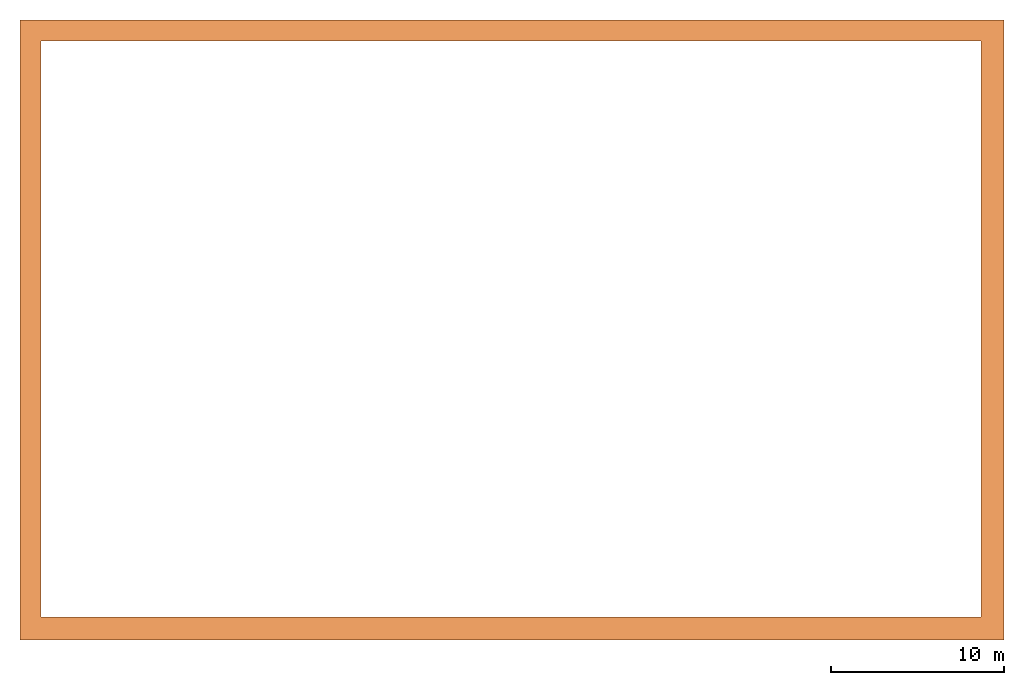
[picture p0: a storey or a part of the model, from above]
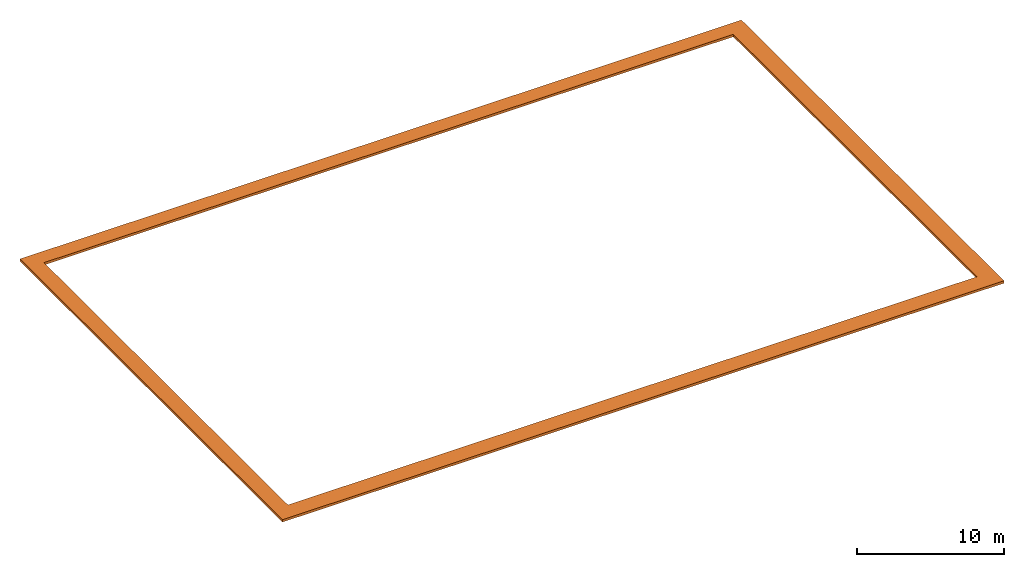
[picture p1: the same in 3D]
Properties of the parts of a building model (IFC4)

# File
Description: ViewDefinition [CoordinationView]
Time: 2026-09-10T21:22:48
Written by: IfcOpenShell 0.8.0
Made in: IfcOpenShell 0.8.0

# IfcBuilding, INNOCEAN
Pset_ConversionAssumptions - ModelStatus: Preliminary - PDF derived, geometry not construction verified; Heights: Storey elevations, slab thickness and facade heights are assumed; Source: 정림3도면_01. 평면도.pdf; 28 pages; X span 53100mm Y span 32600mm

# IfcBuildingStorey (28)
In: INNOCEAN
Name | Elevation (mm)
B8 | -30600
B7 | -27000
B6 | -23400
B5 | -19800
B4 | -16200
B3 | -12600
B2 | -9000
B1 | -5000
F01 | 0
F02 | 6000
F03 | 11000
F04 | 15800
F05 | 20600
F06 | 25400
F07 | 30200
F08 | 34400
F09 | 38600
F10 | 42800
F11 | 47000
F12 | 51200
F13 | 55400
F14 | 59600
F15 | 63800
F16 | 68000
F17 | 72200
F18 | 76400
F19 | 80600
RF | 84800

# IfcBuildingElementProxy (4)
Name | In | Description
F18_Garden_F18_001 | F18 | Simplified footprint from colored landscape area
F19_Garden_F19_001 | F19 | Simplified footprint from colored landscape area
RF_Garden_RF_001 | RF | Simplified footprint from colored landscape area
Site_SiteEdge_001 | Site | Site boundary traced from PDF, no terrain elevations

# IfcColumn (342)
Description: PDF vector recovery
Name | In
B8_Columns_B8_001 | B8
B8_Columns_B8_002 | B8
B8_Columns_B8_003 | B8
B8_Columns_B8_004 | B8
B8_Columns_B8_005 | B8
B8_Columns_B8_006 | B8
B8_Columns_B8_007 | B8
B8_Columns_B8_008 | B8
B8_Columns_B8_009 | B8
B8_Columns_B8_010 | B8
B8_Columns_B8_011 | B8
B8_Columns_B8_012 | B8
B8_Columns_B8_013 | B8
B8_Columns_B8_014 | B8
B8_Columns_B8_015 | B8
B8_Columns_B8_016 | B8
B8_Columns_B8_017 | B8
B8_Columns_B8_018 | B8
B8_Columns_B8_019 | B8
B8_Columns_B8_020 | B8
B8_Columns_B8_021 | B8
B7_Columns_B7_001 | B7
B7_Columns_B7_002 | B7
B7_Columns_B7_003 | B7
B7_Columns_B7_004 | B7
B7_Columns_B7_005 | B7
B7_Columns_B7_006 | B7
B7_Columns_B7_007 | B7
B7_Columns_B7_008 | B7
B7_Columns_B7_009 | B7
B7_Columns_B7_010 | B7
B7_Columns_B7_011 | B7
B7_Columns_B7_012 | B7
B7_Columns_B7_013 | B7
B7_Columns_B7_014 | B7
B7_Columns_B7_015 | B7
B7_Columns_B7_016 | B7
B7_Columns_B7_017 | B7
B7_Columns_B7_018 | B7
B7_Columns_B7_019 | B7
B7_Columns_B7_020 | B7
B7_Columns_B7_021 | B7
B6_Columns_B6_001 | B6
B6_Columns_B6_002 | B6
B6_Columns_B6_003 | B6
B6_Columns_B6_004 | B6
B6_Columns_B6_005 | B6
B6_Columns_B6_006 | B6
B6_Columns_B6_007 | B6
B6_Columns_B6_008 | B6
B6_Columns_B6_009 | B6
B6_Columns_B6_010 | B6
B6_Columns_B6_011 | B6
B6_Columns_B6_012 | B6
B6_Columns_B6_013 | B6
B6_Columns_B6_014 | B6
B6_Columns_B6_015 | B6
B6_Columns_B6_016 | B6
B6_Columns_B6_017 | B6
B6_Columns_B6_018 | B6
B6_Columns_B6_019 | B6
B6_Columns_B6_020 | B6
B6_Columns_B6_021 | B6
B5_Columns_B5_001 | B5
B5_Columns_B5_002 | B5
B5_Columns_B5_003 | B5
B5_Columns_B5_004 | B5
B5_Columns_B5_005 | B5
B5_Columns_B5_006 | B5
B5_Columns_B5_007 | B5
B5_Columns_B5_008 | B5
B5_Columns_B5_009 | B5
B5_Columns_B5_010 | B5
B5_Columns_B5_011 | B5
B5_Columns_B5_012 | B5
B5_Columns_B5_013 | B5
B5_Columns_B5_014 | B5
B5_Columns_B5_015 | B5
B5_Columns_B5_016 | B5
B5_Columns_B5_017 | B5
B5_Columns_B5_018 | B5
B5_Columns_B5_019 | B5
B5_Columns_B5_020 | B5
B5_Columns_B5_021 | B5
B4_Columns_B4_001 | B4
B4_Columns_B4_002 | B4
B4_Columns_B4_003 | B4
B4_Columns_B4_004 | B4
B4_Columns_B4_005 | B4
B4_Columns_B4_006 | B4
B4_Columns_B4_007 | B4
B4_Columns_B4_008 | B4
B4_Columns_B4_009 | B4
B4_Columns_B4_010 | B4
B4_Columns_B4_011 | B4
B4_Columns_B4_012 | B4
B4_Columns_B4_013 | B4
B4_Columns_B4_014 | B4
B4_Columns_B4_015 | B4
B4_Columns_B4_016 | B4
B4_Columns_B4_017 | B4
B4_Columns_B4_018 | B4
B4_Columns_B4_019 | B4
B4_Columns_B4_020 | B4
B3_Columns_B3_001 | B3
B3_Columns_B3_002 | B3
B3_Columns_B3_003 | B3
B3_Columns_B3_004 | B3
B3_Columns_B3_005 | B3
B3_Columns_B3_006 | B3
B3_Columns_B3_007 | B3
B3_Columns_B3_008 | B3
B3_Columns_B3_009 | B3
B3_Columns_B3_010 | B3
B3_Columns_B3_011 | B3
B3_Columns_B3_012 | B3
B3_Columns_B3_013 | B3
B3_Columns_B3_014 | B3
B3_Columns_B3_015 | B3
B3_Columns_B3_016 | B3
B3_Columns_B3_017 | B3
B3_Columns_B3_018 | B3
B3_Columns_B3_019 | B3
B3_Columns_B3_020 | B3
B3_Columns_B3_021 | B3
B2_Columns_B2_001 | B2
B2_Columns_B2_002 | B2
B2_Columns_B2_003 | B2
B2_Columns_B2_004 | B2
B2_Columns_B2_005 | B2
B2_Columns_B2_006 | B2
B2_Columns_B2_007 | B2
B2_Columns_B2_008 | B2
B2_Columns_B2_009 | B2
B2_Columns_B2_010 | B2
B2_Columns_B2_011 | B2
B2_Columns_B2_012 | B2
B1_Columns_B1_001 | B1
B1_Columns_B1_002 | B1
B1_Columns_B1_003 | B1
B1_Columns_B1_004 | B1
B1_Columns_B1_005 | B1
B1_Columns_B1_006 | B1
B1_Columns_B1_007 | B1
B1_Columns_B1_008 | B1
B1_Columns_B1_009 | B1
B1_Columns_B1_010 | B1
B1_Columns_B1_011 | B1
B1_Columns_B1_012 | B1
B1_Columns_B1_013 | B1
B1_Columns_B1_014 | B1
F01_Columns_F01_001 | F01
F01_Columns_F01_002 | F01
F01_Columns_F01_003 | F01
F01_Columns_F01_004 | F01
F01_Columns_F01_005 | F01
F01_Columns_F01_006 | F01
F01_Columns_F01_007 | F01
F01_Columns_F01_008 | F01
F01_Columns_F01_009 | F01
F01_Columns_F01_010 | F01
F01_Columns_F01_011 | F01
F02_Columns_F02_001 | F02
F02_Columns_F02_002 | F02
F02_Columns_F02_003 | F02
F02_Columns_F02_004 | F02
F02_Columns_F02_005 | F02
F02_Columns_F02_006 | F02
F02_Columns_F02_007 | F02
F02_Columns_F02_008 | F02
F02_Columns_F02_009 | F02
F02_Columns_F02_010 | F02
F03_Columns_F03_001 | F03
F03_Columns_F03_002 | F03
F03_Columns_F03_003 | F03
F03_Columns_F03_004 | F03
F03_Columns_F03_005 | F03
F03_Columns_F03_006 | F03
F03_Columns_F03_007 | F03
F03_Columns_F03_008 | F03
F03_Columns_F03_009 | F03
F03_Columns_F03_010 | F03
F04_Columns_F04_001 | F04
F04_Columns_F04_002 | F04
F04_Columns_F04_003 | F04
F04_Columns_F04_004 | F04
F04_Columns_F04_005 | F04
F04_Columns_F04_006 | F04
F04_Columns_F04_007 | F04
F04_Columns_F04_008 | F04
F04_Columns_F04_009 | F04
F04_Columns_F04_010 | F04
F05_Columns_F05_001 | F05
F05_Columns_F05_002 | F05
F05_Columns_F05_003 | F05
F05_Columns_F05_004 | F05
F05_Columns_F05_005 | F05
F05_Columns_F05_006 | F05
F05_Columns_F05_007 | F05
F05_Columns_F05_008 | F05
F05_Columns_F05_009 | F05
F05_Columns_F05_010 | F05
F05_Columns_F05_011 | F05
F06_Columns_F06_001 | F06
F06_Columns_F06_002 | F06
F06_Columns_F06_003 | F06
F06_Columns_F06_004 | F06
F06_Columns_F06_005 | F06
F06_Columns_F06_006 | F06
F06_Columns_F06_007 | F06
F06_Columns_F06_008 | F06
F06_Columns_F06_009 | F06
F06_Columns_F06_010 | F06
F07_Columns_F07_001 | F07
F07_Columns_F07_002 | F07
F07_Columns_F07_003 | F07
F07_Columns_F07_004 | F07
F07_Columns_F07_005 | F07
F07_Columns_F07_006 | F07
F07_Columns_F07_007 | F07
F07_Columns_F07_008 | F07
F07_Columns_F07_009 | F07
F07_Columns_F07_010 | F07
F08_Columns_F08_001 | F08
F08_Columns_F08_002 | F08
F08_Columns_F08_003 | F08
F08_Columns_F08_004 | F08
F08_Columns_F08_005 | F08
F08_Columns_F08_006 | F08
F08_Columns_F08_007 | F08
F08_Columns_F08_008 | F08
F08_Columns_F08_009 | F08
F08_Columns_F08_010 | F08
F09_Columns_F09_001 | F09
F09_Columns_F09_002 | F09
F09_Columns_F09_003 | F09
F09_Columns_F09_004 | F09
F09_Columns_F09_005 | F09
F09_Columns_F09_006 | F09
F09_Columns_F09_007 | F09
F09_Columns_F09_008 | F09
F09_Columns_F09_009 | F09
F09_Columns_F09_010 | F09
F10_Columns_F10_001 | F10
F10_Columns_F10_002 | F10
F10_Columns_F10_003 | F10
F10_Columns_F10_004 | F10
F10_Columns_F10_005 | F10
F10_Columns_F10_006 | F10
F10_Columns_F10_007 | F10
F10_Columns_F10_008 | F10
F10_Columns_F10_009 | F10
F10_Columns_F10_010 | F10
F11_Columns_F11_001 | F11
F11_Columns_F11_002 | F11
F11_Columns_F11_003 | F11
F11_Columns_F11_004 | F11
F11_Columns_F11_005 | F11
F11_Columns_F11_006 | F11
F11_Columns_F11_007 | F11
F11_Columns_F11_008 | F11
F11_Columns_F11_009 | F11
F11_Columns_F11_010 | F11
F12_Columns_F12_001 | F12
F12_Columns_F12_002 | F12
F12_Columns_F12_003 | F12
F12_Columns_F12_004 | F12
F12_Columns_F12_005 | F12
F12_Columns_F12_006 | F12
F12_Columns_F12_007 | F12
F12_Columns_F12_008 | F12
F12_Columns_F12_009 | F12
F12_Columns_F12_010 | F12
F13_Columns_F13_001 | F13
F13_Columns_F13_002 | F13
F13_Columns_F13_003 | F13
F13_Columns_F13_004 | F13
F13_Columns_F13_005 | F13
F13_Columns_F13_006 | F13
F13_Columns_F13_007 | F13
F13_Columns_F13_008 | F13
F13_Columns_F13_009 | F13
F13_Columns_F13_010 | F13
F14_Columns_F14_001 | F14
F14_Columns_F14_002 | F14
F14_Columns_F14_003 | F14
F14_Columns_F14_004 | F14
F14_Columns_F14_005 | F14
F14_Columns_F14_006 | F14
F14_Columns_F14_007 | F14
F14_Columns_F14_008 | F14
F14_Columns_F14_009 | F14
F14_Columns_F14_010 | F14
F15_Columns_F15_001 | F15
F15_Columns_F15_002 | F15
F15_Columns_F15_003 | F15
F15_Columns_F15_004 | F15
F15_Columns_F15_005 | F15
F15_Columns_F15_006 | F15
F15_Columns_F15_007 | F15
F15_Columns_F15_008 | F15
F15_Columns_F15_009 | F15
F15_Columns_F15_010 | F15
F16_Columns_F16_001 | F16
F16_Columns_F16_002 | F16
F16_Columns_F16_003 | F16
F16_Columns_F16_004 | F16
F16_Columns_F16_005 | F16
F16_Columns_F16_006 | F16
F16_Columns_F16_007 | F16
F16_Columns_F16_008 | F16
F16_Columns_F16_009 | F16
F16_Columns_F16_010 | F16
F17_Columns_F17_001 | F17
F17_Columns_F17_002 | F17
F17_Columns_F17_003 | F17
F17_Columns_F17_004 | F17
F17_Columns_F17_005 | F17
F17_Columns_F17_006 | F17
F17_Columns_F17_007 | F17
F17_Columns_F17_008 | F17
F17_Columns_F17_009 | F17
F17_Columns_F17_010 | F17
F18_Columns_F18_001 | F18
F18_Columns_F18_002 | F18
F18_Columns_F18_003 | F18
F18_Columns_F18_004 | F18
F18_Columns_F18_005 | F18
F18_Columns_F18_006 | F18
F18_Columns_F18_007 | F18
F18_Columns_F18_008 | F18
F18_Columns_F18_009 | F18
F18_Columns_F18_010 | F18
F19_Columns_F19_001 | F19
F19_Columns_F19_002 | F19
F19_Columns_F19_003 | F19
F19_Columns_F19_004 | F19
F19_Columns_F19_005 | F19
F19_Columns_F19_006 | F19
F19_Columns_F19_007 | F19
F19_Columns_F19_008 | F19
F19_Columns_F19_009 | F19

# IfcCurtainWall (72)
Description: Plan envelope; generic transparent facade, no elevation data
Name | In
F02_Facade_F02_001 | F02
F02_Facade_F02_002 | F02
F02_Facade_F02_003 | F02
F02_Facade_F02_004 | F02
F03_Facade_F03_001 | F03
F03_Facade_F03_002 | F03
F03_Facade_F03_003 | F03
F03_Facade_F03_004 | F03
F04_Facade_F04_001 | F04
F04_Facade_F04_002 | F04
F04_Facade_F04_003 | F04
F04_Facade_F04_004 | F04
F05_Facade_F05_001 | F05
F05_Facade_F05_002 | F05
F05_Facade_F05_003 | F05
F05_Facade_F05_004 | F05
F06_Facade_F06_001 | F06
F06_Facade_F06_002 | F06
F06_Facade_F06_003 | F06
F06_Facade_F06_004 | F06
F07_Facade_F07_001 | F07
F07_Facade_F07_002 | F07
F07_Facade_F07_003 | F07
F07_Facade_F07_004 | F07
F08_Facade_F08_001 | F08
F08_Facade_F08_002 | F08
F08_Facade_F08_003 | F08
F08_Facade_F08_004 | F08
F09_Facade_F09_001 | F09
F09_Facade_F09_002 | F09
F09_Facade_F09_003 | F09
F09_Facade_F09_004 | F09
F10_Facade_F10_001 | F10
F10_Facade_F10_002 | F10
F10_Facade_F10_003 | F10
F10_Facade_F10_004 | F10
F11_Facade_F11_001 | F11
F11_Facade_F11_002 | F11
F11_Facade_F11_003 | F11
F11_Facade_F11_004 | F11
F12_Facade_F12_001 | F12
F12_Facade_F12_002 | F12
F12_Facade_F12_003 | F12
F12_Facade_F12_004 | F12
F13_Facade_F13_001 | F13
F13_Facade_F13_002 | F13
F13_Facade_F13_003 | F13
F13_Facade_F13_004 | F13
F14_Facade_F14_001 | F14
F14_Facade_F14_002 | F14
F14_Facade_F14_003 | F14
F14_Facade_F14_004 | F14
F15_Facade_F15_001 | F15
F15_Facade_F15_002 | F15
F15_Facade_F15_003 | F15
F15_Facade_F15_004 | F15
F16_Facade_F16_001 | F16
F16_Facade_F16_002 | F16
F16_Facade_F16_003 | F16
F16_Facade_F16_004 | F16
F17_Facade_F17_001 | F17
F17_Facade_F17_002 | F17
F17_Facade_F17_003 | F17
F17_Facade_F17_004 | F17
F18_Facade_F18_001 | F18
F18_Facade_F18_002 | F18
F18_Facade_F18_003 | F18
F18_Facade_F18_004 | F18
F19_Facade_F19_001 | F19
F19_Facade_F19_002 | F19
F19_Facade_F19_003 | F19
F19_Facade_F19_004 | F19

# IfcSlab (28)
Description: Footprint and voids visually traced; thickness assumed 250 mm
Name | In
B8_Slab_B8_001 | B8
B7_Slab_B7_001 | B7
B6_Slab_B6_001 | B6
B5_Slab_B5_001 | B5
B4_Slab_B4_001 | B4
B3_Slab_B3_001 | B3
B2_Slab_B2_001 | B2
B1_Slab_B1_001 | B1
F01_Slab_F01_001 | F01
F02_Slab_F02_001 | F02
F03_Slab_F03_001 | F03
F04_Slab_F04_001 | F04
F05_Slab_F05_001 | F05
F06_Slab_F06_001 | F06
F07_Slab_F07_001 | F07
F08_Slab_F08_001 | F08
F09_Slab_F09_001 | F09
F10_Slab_F10_001 | F10
F11_Slab_F11_001 | F11
F12_Slab_F12_001 | F12
F13_Slab_F13_001 | F13
F14_Slab_F14_001 | F14
F15_Slab_F15_001 | F15
F16_Slab_F16_001 | F16
F17_Slab_F17_001 | F17
F18_Slab_F18_001 | F18
F19_Slab_F19_001 | F19
RF_Slab_RF_001 | RF

# IfcWall (2039)
Description: Wall-layer closed loops and paired parallel lines 75-425 mm; incomplete/unclassified partitions remain in reference
Name | In
B8_Walls_B8_001 | B8
B8_Walls_B8_002 | B8
B8_Walls_B8_003 | B8
B8_Walls_B8_004 | B8
B8_Walls_B8_005 | B8
B8_Walls_B8_006 | B8
B8_Walls_B8_007 | B8
B8_Walls_B8_008 | B8
B8_Walls_B8_009 | B8
B8_Walls_B8_010 | B8
B8_Walls_B8_011 | B8
B8_Walls_B8_012 | B8
B8_Walls_B8_013 | B8
B8_Walls_B8_014 | B8
B8_Walls_B8_015 | B8
B8_Walls_B8_016 | B8
B8_Walls_B8_017 | B8
B8_Walls_B8_018 | B8
B8_Walls_B8_019 | B8
B8_Walls_B8_020 | B8
B8_Walls_B8_021 | B8
B8_Walls_B8_022 | B8
B8_Walls_B8_023 | B8
B8_Walls_B8_024 | B8
B8_Walls_B8_025 | B8
B8_Walls_B8_026 | B8
B8_Walls_B8_027 | B8
B8_Walls_B8_028 | B8
B8_Walls_B8_029 | B8
B8_Walls_B8_030 | B8
B8_Walls_B8_031 | B8
B8_Walls_B8_032 | B8
B8_Walls_B8_033 | B8
B8_Walls_B8_034 | B8
B8_Walls_B8_035 | B8
B8_Walls_B8_036 | B8
B8_Walls_B8_037 | B8
B8_Walls_B8_038 | B8
B8_Walls_B8_039 | B8
B8_Walls_B8_040 | B8
B8_Walls_B8_041 | B8
B8_Walls_B8_042 | B8
B8_Walls_B8_043 | B8
B8_Walls_B8_044 | B8
B8_Walls_B8_045 | B8
B8_Walls_B8_046 | B8
B8_Walls_B8_047 | B8
B8_Walls_B8_048 | B8
B8_Walls_B8_049 | B8
B8_Walls_B8_050 | B8
B8_Walls_B8_051 | B8
B8_Walls_B8_052 | B8
B8_Walls_B8_053 | B8
B8_Walls_B8_054 | B8
B8_Walls_B8_055 | B8
B8_Walls_B8_056 | B8
B8_Walls_B8_057 | B8
B8_Walls_B8_058 | B8
B8_Walls_B8_059 | B8
B8_Walls_B8_060 | B8
B8_Walls_B8_061 | B8
B8_Walls_B8_062 | B8
B8_Walls_B8_063 | B8
B7_Walls_B7_001 | B7
B7_Walls_B7_002 | B7
B7_Walls_B7_003 | B7
B7_Walls_B7_004 | B7
B7_Walls_B7_005 | B7
B7_Walls_B7_006 | B7
B7_Walls_B7_007 | B7
B7_Walls_B7_008 | B7
B7_Walls_B7_009 | B7
B7_Walls_B7_010 | B7
B7_Walls_B7_011 | B7
B7_Walls_B7_012 | B7
B7_Walls_B7_013 | B7
B7_Walls_B7_014 | B7
B7_Walls_B7_015 | B7
B7_Walls_B7_016 | B7
B7_Walls_B7_017 | B7
B7_Walls_B7_018 | B7
B7_Walls_B7_019 | B7
B7_Walls_B7_020 | B7
B7_Walls_B7_021 | B7
B7_Walls_B7_022 | B7
B7_Walls_B7_023 | B7
B7_Walls_B7_024 | B7
B7_Walls_B7_025 | B7
B7_Walls_B7_026 | B7
B7_Walls_B7_027 | B7
B7_Walls_B7_028 | B7
B7_Walls_B7_029 | B7
B7_Walls_B7_030 | B7
B7_Walls_B7_031 | B7
B7_Walls_B7_032 | B7
B7_Walls_B7_033 | B7
B7_Walls_B7_034 | B7
B7_Walls_B7_035 | B7
B7_Walls_B7_036 | B7
B7_Walls_B7_037 | B7
B7_Walls_B7_038 | B7
B7_Walls_B7_039 | B7
B7_Walls_B7_040 | B7
B7_Walls_B7_041 | B7
B7_Walls_B7_042 | B7
B7_Walls_B7_043 | B7
B7_Walls_B7_044 | B7
B7_Walls_B7_045 | B7
B7_Walls_B7_046 | B7
B7_Walls_B7_047 | B7
B7_Walls_B7_048 | B7
B7_Walls_B7_049 | B7
B7_Walls_B7_050 | B7
B7_Walls_B7_051 | B7
B7_Walls_B7_052 | B7
B7_Walls_B7_053 | B7
B7_Walls_B7_054 | B7
B7_Walls_B7_055 | B7
B7_Walls_B7_056 | B7
B6_Walls_B6_001 | B6
B6_Walls_B6_002 | B6
B6_Walls_B6_003 | B6
B6_Walls_B6_004 | B6
B6_Walls_B6_005 | B6
B6_Walls_B6_006 | B6
B6_Walls_B6_007 | B6
B6_Walls_B6_008 | B6
B6_Walls_B6_009 | B6
B6_Walls_B6_010 | B6
B6_Walls_B6_011 | B6
B6_Walls_B6_012 | B6
B6_Walls_B6_013 | B6
B6_Walls_B6_014 | B6
B6_Walls_B6_015 | B6
B6_Walls_B6_016 | B6
B6_Walls_B6_017 | B6
B6_Walls_B6_018 | B6
B6_Walls_B6_019 | B6
B6_Walls_B6_020 | B6
B6_Walls_B6_021 | B6
B6_Walls_B6_022 | B6
B6_Walls_B6_023 | B6
B6_Walls_B6_024 | B6
B6_Walls_B6_025 | B6
B6_Walls_B6_026 | B6
B6_Walls_B6_027 | B6
B6_Walls_B6_028 | B6
B6_Walls_B6_029 | B6
B6_Walls_B6_030 | B6
B6_Walls_B6_031 | B6
B6_Walls_B6_032 | B6
B6_Walls_B6_033 | B6
B6_Walls_B6_034 | B6
B6_Walls_B6_035 | B6
B6_Walls_B6_036 | B6
B6_Walls_B6_037 | B6
B6_Walls_B6_038 | B6
B6_Walls_B6_039 | B6
B6_Walls_B6_040 | B6
B6_Walls_B6_041 | B6
B6_Walls_B6_042 | B6
B6_Walls_B6_043 | B6
B6_Walls_B6_044 | B6
B6_Walls_B6_045 | B6
B6_Walls_B6_046 | B6
B6_Walls_B6_047 | B6
B6_Walls_B6_048 | B6
B6_Walls_B6_049 | B6
B6_Walls_B6_050 | B6
B6_Walls_B6_051 | B6
B6_Walls_B6_052 | B6
B6_Walls_B6_053 | B6
B6_Walls_B6_054 | B6
B6_Walls_B6_055 | B6
B6_Walls_B6_056 | B6
B6_Walls_B6_057 | B6
B6_Walls_B6_058 | B6
B6_Walls_B6_059 | B6
B6_Walls_B6_060 | B6
B6_Walls_B6_061 | B6
B5_Walls_B5_001 | B5
B5_Walls_B5_002 | B5
B5_Walls_B5_003 | B5
B5_Walls_B5_004 | B5
B5_Walls_B5_005 | B5
B5_Walls_B5_006 | B5
B5_Walls_B5_007 | B5
B5_Walls_B5_008 | B5
B5_Walls_B5_009 | B5
B5_Walls_B5_010 | B5
B5_Walls_B5_011 | B5
B5_Walls_B5_012 | B5
B5_Walls_B5_013 | B5
B5_Walls_B5_014 | B5
B5_Walls_B5_015 | B5
B5_Walls_B5_016 | B5
B5_Walls_B5_017 | B5
B5_Walls_B5_018 | B5
B5_Walls_B5_019 | B5
B5_Walls_B5_020 | B5
B5_Walls_B5_021 | B5
B5_Walls_B5_022 | B5
B5_Walls_B5_023 | B5
B5_Walls_B5_024 | B5
B5_Walls_B5_025 | B5
B5_Walls_B5_026 | B5
B5_Walls_B5_027 | B5
B5_Walls_B5_028 | B5
B5_Walls_B5_029 | B5
B5_Walls_B5_030 | B5
B5_Walls_B5_031 | B5
B5_Walls_B5_032 | B5
B5_Walls_B5_033 | B5
B5_Walls_B5_034 | B5
B5_Walls_B5_035 | B5
B5_Walls_B5_036 | B5
B5_Walls_B5_037 | B5
B5_Walls_B5_038 | B5
B5_Walls_B5_039 | B5
B5_Walls_B5_040 | B5
B5_Walls_B5_041 | B5
B5_Walls_B5_042 | B5
B5_Walls_B5_043 | B5
B5_Walls_B5_044 | B5
B5_Walls_B5_045 | B5
B5_Walls_B5_046 | B5
B5_Walls_B5_047 | B5
B5_Walls_B5_048 | B5
B5_Walls_B5_049 | B5
B5_Walls_B5_050 | B5
B5_Walls_B5_051 | B5
B5_Walls_B5_052 | B5
B5_Walls_B5_053 | B5
B5_Walls_B5_054 | B5
B5_Walls_B5_055 | B5
B5_Walls_B5_056 | B5
B5_Walls_B5_057 | B5
B5_Walls_B5_058 | B5
B5_Walls_B5_059 | B5
B5_Walls_B5_060 | B5
B5_Walls_B5_061 | B5
B4_Walls_B4_001 | B4
B4_Walls_B4_002 | B4
B4_Walls_B4_003 | B4
B4_Walls_B4_004 | B4
B4_Walls_B4_005 | B4
B4_Walls_B4_006 | B4
B4_Walls_B4_007 | B4
B4_Walls_B4_008 | B4
B4_Walls_B4_009 | B4
B4_Walls_B4_010 | B4
B4_Walls_B4_011 | B4
B4_Walls_B4_012 | B4
B4_Walls_B4_013 | B4
B4_Walls_B4_014 | B4
B4_Walls_B4_015 | B4
B4_Walls_B4_016 | B4
B4_Walls_B4_017 | B4
B4_Walls_B4_018 | B4
B4_Walls_B4_019 | B4
B4_Walls_B4_020 | B4
B4_Walls_B4_021 | B4
B4_Walls_B4_022 | B4
B4_Walls_B4_023 | B4
B4_Walls_B4_024 | B4
B4_Walls_B4_025 | B4
B4_Walls_B4_026 | B4
B4_Walls_B4_027 | B4
B4_Walls_B4_028 | B4
B4_Walls_B4_029 | B4
B4_Walls_B4_030 | B4
B4_Walls_B4_031 | B4
B4_Walls_B4_032 | B4
B4_Walls_B4_033 | B4
B4_Walls_B4_034 | B4
B4_Walls_B4_035 | B4
B4_Walls_B4_036 | B4
B4_Walls_B4_037 | B4
B4_Walls_B4_038 | B4
B4_Walls_B4_039 | B4
B4_Walls_B4_040 | B4
B4_Walls_B4_041 | B4
B4_Walls_B4_042 | B4
B4_Walls_B4_043 | B4
B4_Walls_B4_044 | B4
B4_Walls_B4_045 | B4
B4_Walls_B4_046 | B4
B4_Walls_B4_047 | B4
B4_Walls_B4_048 | B4
B4_Walls_B4_049 | B4
B4_Walls_B4_050 | B4
B4_Walls_B4_051 | B4
B4_Walls_B4_052 | B4
B4_Walls_B4_053 | B4
B4_Walls_B4_054 | B4
B4_Walls_B4_055 | B4
B4_Walls_B4_056 | B4
B4_Walls_B4_057 | B4
B4_Walls_B4_058 | B4
B4_Walls_B4_059 | B4
B4_Walls_B4_060 | B4
B4_Walls_B4_061 | B4
B3_Walls_B3_001 | B3
B3_Walls_B3_002 | B3
B3_Walls_B3_003 | B3
B3_Walls_B3_004 | B3
B3_Walls_B3_005 | B3
B3_Walls_B3_006 | B3
B3_Walls_B3_007 | B3
B3_Walls_B3_008 | B3
B3_Walls_B3_009 | B3
B3_Walls_B3_010 | B3
B3_Walls_B3_011 | B3
B3_Walls_B3_012 | B3
B3_Walls_B3_013 | B3
B3_Walls_B3_014 | B3
B3_Walls_B3_015 | B3
B3_Walls_B3_016 | B3
B3_Walls_B3_017 | B3
B3_Walls_B3_018 | B3
B3_Walls_B3_019 | B3
B3_Walls_B3_020 | B3
B3_Walls_B3_021 | B3
B3_Walls_B3_022 | B3
B3_Walls_B3_023 | B3
B3_Walls_B3_024 | B3
B3_Walls_B3_025 | B3
B3_Walls_B3_026 | B3
B3_Walls_B3_027 | B3
B3_Walls_B3_028 | B3
B3_Walls_B3_029 | B3
B3_Walls_B3_030 | B3
B3_Walls_B3_031 | B3
B3_Walls_B3_032 | B3
B3_Walls_B3_033 | B3
B3_Walls_B3_034 | B3
B3_Walls_B3_035 | B3
B3_Walls_B3_036 | B3
B3_Walls_B3_037 | B3
B3_Walls_B3_038 | B3
B3_Walls_B3_039 | B3
B3_Walls_B3_040 | B3
B3_Walls_B3_041 | B3
B3_Walls_B3_042 | B3
B3_Walls_B3_043 | B3
B3_Walls_B3_044 | B3
B3_Walls_B3_045 | B3
B3_Walls_B3_046 | B3
B3_Walls_B3_047 | B3
B3_Walls_B3_048 | B3
B3_Walls_B3_049 | B3
B3_Walls_B3_050 | B3
B3_Walls_B3_051 | B3
B3_Walls_B3_052 | B3
B3_Walls_B3_053 | B3
B3_Walls_B3_054 | B3
B3_Walls_B3_055 | B3
B3_Walls_B3_056 | B3
B3_Walls_B3_057 | B3
B3_Walls_B3_058 | B3
B3_Walls_B3_059 | B3
B3_Walls_B3_060 | B3
B3_Walls_B3_061 | B3
B2_Walls_B2_001 | B2
B2_Walls_B2_002 | B2
B2_Walls_B2_003 | B2
B2_Walls_B2_004 | B2
B2_Walls_B2_005 | B2
B2_Walls_B2_006 | B2
B2_Walls_B2_007 | B2
B2_Walls_B2_008 | B2
B2_Walls_B2_009 | B2
B2_Walls_B2_010 | B2
B2_Walls_B2_011 | B2
B2_Walls_B2_012 | B2
B2_Walls_B2_013 | B2
B2_Walls_B2_014 | B2
B2_Walls_B2_015 | B2
B2_Walls_B2_016 | B2
B2_Walls_B2_017 | B2
B2_Walls_B2_018 | B2
B2_Walls_B2_019 | B2
B2_Walls_B2_020 | B2
B2_Walls_B2_021 | B2
B2_Walls_B2_022 | B2
B2_Walls_B2_023 | B2
B2_Walls_B2_024 | B2
B2_Walls_B2_025 | B2
B2_Walls_B2_026 | B2
B2_Walls_B2_027 | B2
B2_Walls_B2_028 | B2
B2_Walls_B2_029 | B2
B2_Walls_B2_030 | B2
B2_Walls_B2_031 | B2
B2_Walls_B2_032 | B2
B2_Walls_B2_033 | B2
B2_Walls_B2_034 | B2
B2_Walls_B2_035 | B2
B2_Walls_B2_036 | B2
B2_Walls_B2_037 | B2
B2_Walls_B2_038 | B2
B2_Walls_B2_039 | B2
B2_Walls_B2_040 | B2
B2_Walls_B2_041 | B2
B2_Walls_B2_042 | B2
B2_Walls_B2_043 | B2
B2_Walls_B2_044 | B2
B2_Walls_B2_045 | B2
B2_Walls_B2_046 | B2
B2_Walls_B2_047 | B2
B2_Walls_B2_048 | B2
B2_Walls_B2_049 | B2
B2_Walls_B2_050 | B2
B2_Walls_B2_051 | B2
B2_Walls_B2_052 | B2
B2_Walls_B2_053 | B2
B2_Walls_B2_054 | B2
B2_Walls_B2_055 | B2
B2_Walls_B2_056 | B2
B2_Walls_B2_057 | B2
B2_Walls_B2_058 | B2
B2_Walls_B2_059 | B2
B2_Walls_B2_060 | B2
B2_Walls_B2_061 | B2
B2_Walls_B2_062 | B2
B1_Walls_B1_001 | B1
B1_Walls_B1_002 | B1
B1_Walls_B1_003 | B1
B1_Walls_B1_004 | B1
B1_Walls_B1_005 | B1
B1_Walls_B1_006 | B1
B1_Walls_B1_007 | B1
B1_Walls_B1_008 | B1
B1_Walls_B1_009 | B1
B1_Walls_B1_010 | B1
B1_Walls_B1_011 | B1
B1_Walls_B1_012 | B1
B1_Walls_B1_013 | B1
B1_Walls_B1_014 | B1
B1_Walls_B1_015 | B1
B1_Walls_B1_016 | B1
B1_Walls_B1_017 | B1
B1_Walls_B1_018 | B1
B1_Walls_B1_019 | B1
B1_Walls_B1_020 | B1
B1_Walls_B1_021 | B1
B1_Walls_B1_022 | B1
B1_Walls_B1_023 | B1
B1_Walls_B1_024 | B1
B1_Walls_B1_025 | B1
B1_Walls_B1_026 | B1
B1_Walls_B1_027 | B1
B1_Walls_B1_028 | B1
B1_Walls_B1_029 | B1
B1_Walls_B1_030 | B1
B1_Walls_B1_031 | B1
B1_Walls_B1_032 | B1
B1_Walls_B1_033 | B1
B1_Walls_B1_034 | B1
B1_Walls_B1_035 | B1
B1_Walls_B1_036 | B1
B1_Walls_B1_037 | B1
B1_Walls_B1_038 | B1
B1_Walls_B1_039 | B1
B1_Walls_B1_040 | B1
B1_Walls_B1_041 | B1
B1_Walls_B1_042 | B1
B1_Walls_B1_043 | B1
B1_Walls_B1_044 | B1
B1_Walls_B1_045 | B1
B1_Walls_B1_046 | B1
B1_Walls_B1_047 | B1
B1_Walls_B1_048 | B1
B1_Walls_B1_049 | B1
B1_Walls_B1_050 | B1
B1_Walls_B1_051 | B1
B1_Walls_B1_052 | B1
B1_Walls_B1_053 | B1
B1_Walls_B1_054 | B1
B1_Walls_B1_055 | B1
B1_Walls_B1_056 | B1
B1_Walls_B1_057 | B1
B1_Walls_B1_058 | B1
B1_Walls_B1_059 | B1
B1_Walls_B1_060 | B1
B1_Walls_B1_061 | B1
B1_Walls_B1_062 | B1
B1_Walls_B1_063 | B1
B1_Walls_B1_064 | B1
B1_Walls_B1_065 | B1
B1_Walls_B1_066 | B1
B1_Walls_B1_067 | B1
B1_Walls_B1_068 | B1
B1_Walls_B1_069 | B1
B1_Walls_B1_070 | B1
B1_Walls_B1_071 | B1
B1_Walls_B1_072 | B1
B1_Walls_B1_073 | B1
B1_Walls_B1_074 | B1
F01_Walls_F01_001 | F01
F01_Walls_F01_002 | F01
F01_Walls_F01_003 | F01
F01_Walls_F01_004 | F01
F01_Walls_F01_005 | F01
F01_Walls_F01_006 | F01
F01_Walls_F01_007 | F01
F01_Walls_F01_008 | F01
F01_Walls_F01_009 | F01
F01_Walls_F01_010 | F01
F01_Walls_F01_011 | F01
F01_Walls_F01_012 | F01
F01_Walls_F01_013 | F01
F01_Walls_F01_014 | F01
F01_Walls_F01_015 | F01
F01_Walls_F01_016 | F01
F01_Walls_F01_017 | F01
F01_Walls_F01_018 | F01
F01_Walls_F01_019 | F01
F01_Walls_F01_020 | F01
F01_Walls_F01_021 | F01
F01_Walls_F01_022 | F01
F01_Walls_F01_023 | F01
F01_Walls_F01_024 | F01
F01_Walls_F01_025 | F01
F01_Walls_F01_026 | F01
F01_Walls_F01_027 | F01
F01_Walls_F01_028 | F01
F01_Walls_F01_029 | F01
F01_Walls_F01_030 | F01
F01_Walls_F01_031 | F01
F01_Walls_F01_032 | F01
F01_Walls_F01_033 | F01
F01_Walls_F01_034 | F01
F01_Walls_F01_035 | F01
F01_Walls_F01_036 | F01
F01_Walls_F01_037 | F01
F01_Walls_F01_038 | F01
F01_Walls_F01_039 | F01
F01_Walls_F01_040 | F01
F01_Walls_F01_041 | F01
F01_Walls_F01_042 | F01
F01_Walls_F01_043 | F01
F01_Walls_F01_044 | F01
F01_Walls_F01_045 | F01
F01_Walls_F01_046 | F01
F01_Walls_F01_047 | F01
F01_Walls_F01_048 | F01
F01_Walls_F01_049 | F01
F01_Walls_F01_050 | F01
F01_Walls_F01_051 | F01
F01_Walls_F01_052 | F01
F01_Walls_F01_053 | F01
F01_Walls_F01_054 | F01
F01_Walls_F01_055 | F01
F01_Walls_F01_056 | F01
F01_Walls_F01_057 | F01
F01_Walls_F01_058 | F01
F01_Walls_F01_059 | F01
F01_Walls_F01_060 | F01
F01_Walls_F01_061 | F01
F01_Walls_F01_062 | F01
F01_Walls_F01_063 | F01
F01_Walls_F01_064 | F01
F02_Walls_F02_001 | F02
F02_Walls_F02_002 | F02
F02_Walls_F02_003 | F02
F02_Walls_F02_004 | F02
F02_Walls_F02_005 | F02
F02_Walls_F02_006 | F02
F02_Walls_F02_007 | F02
F02_Walls_F02_008 | F02
F02_Walls_F02_009 | F02
F02_Walls_F02_010 | F02
F02_Walls_F02_011 | F02
F02_Walls_F02_012 | F02
F02_Walls_F02_013 | F02
F02_Walls_F02_014 | F02
F02_Walls_F02_015 | F02
F02_Walls_F02_016 | F02
F02_Walls_F02_017 | F02
F02_Walls_F02_018 | F02
F02_Walls_F02_019 | F02
F02_Walls_F02_020 | F02
F02_Walls_F02_021 | F02
F02_Walls_F02_022 | F02
F02_Walls_F02_023 | F02
F02_Walls_F02_024 | F02
F02_Walls_F02_025 | F02
F02_Walls_F02_026 | F02
F02_Walls_F02_027 | F02
F02_Walls_F02_028 | F02
F02_Walls_F02_029 | F02
F02_Walls_F02_030 | F02
F02_Walls_F02_031 | F02
F02_Walls_F02_032 | F02
F02_Walls_F02_033 | F02
F02_Walls_F02_034 | F02
F02_Walls_F02_035 | F02
F02_Walls_F02_036 | F02
F02_Walls_F02_037 | F02
F02_Walls_F02_038 | F02
F02_Walls_F02_039 | F02
F02_Walls_F02_040 | F02
F02_Walls_F02_041 | F02
F02_Walls_F02_042 | F02
F02_Walls_F02_043 | F02
F02_Walls_F02_044 | F02
F02_Walls_F02_045 | F02
F02_Walls_F02_046 | F02
F02_Walls_F02_047 | F02
F02_Walls_F02_048 | F02
F02_Walls_F02_049 | F02
F02_Walls_F02_050 | F02
F02_Walls_F02_051 | F02
F02_Walls_F02_052 | F02
F02_Walls_F02_053 | F02
F02_Walls_F02_054 | F02
F02_Walls_F02_055 | F02
F02_Walls_F02_056 | F02
F02_Walls_F02_057 | F02
F02_Walls_F02_058 | F02
F02_Walls_F02_059 | F02
F02_Walls_F02_060 | F02
F02_Walls_F02_061 | F02
F02_Walls_F02_062 | F02
F03_Walls_F03_001 | F03
F03_Walls_F03_002 | F03
F03_Walls_F03_003 | F03
F03_Walls_F03_004 | F03
F03_Walls_F03_005 | F03
F03_Walls_F03_006 | F03
F03_Walls_F03_007 | F03
F03_Walls_F03_008 | F03
F03_Walls_F03_009 | F03
F03_Walls_F03_010 | F03
F03_Walls_F03_011 | F03
F03_Walls_F03_012 | F03
F03_Walls_F03_013 | F03
F03_Walls_F03_014 | F03
F03_Walls_F03_015 | F03
F03_Walls_F03_016 | F03
F03_Walls_F03_017 | F03
F03_Walls_F03_018 | F03
F03_Walls_F03_019 | F03
F03_Walls_F03_020 | F03
F03_Walls_F03_021 | F03
F03_Walls_F03_022 | F03
F03_Walls_F03_023 | F03
F03_Walls_F03_024 | F03
F03_Walls_F03_025 | F03
F03_Walls_F03_026 | F03
F03_Walls_F03_027 | F03
F03_Walls_F03_028 | F03
F03_Walls_F03_029 | F03
F03_Walls_F03_030 | F03
F03_Walls_F03_031 | F03
F03_Walls_F03_032 | F03
F03_Walls_F03_033 | F03
F03_Walls_F03_034 | F03
F03_Walls_F03_035 | F03
F03_Walls_F03_036 | F03
F03_Walls_F03_037 | F03
F03_Walls_F03_038 | F03
F03_Walls_F03_039 | F03
F03_Walls_F03_040 | F03
F03_Walls_F03_041 | F03
F03_Walls_F03_042 | F03
F03_Walls_F03_043 | F03
F03_Walls_F03_044 | F03
F03_Walls_F03_045 | F03
F03_Walls_F03_046 | F03
F03_Walls_F03_047 | F03
F03_Walls_F03_048 | F03
F03_Walls_F03_049 | F03
F03_Walls_F03_050 | F03
F03_Walls_F03_051 | F03
F03_Walls_F03_052 | F03
F03_Walls_F03_053 | F03
F03_Walls_F03_054 | F03
F03_Walls_F03_055 | F03
F03_Walls_F03_056 | F03
F03_Walls_F03_057 | F03
F03_Walls_F03_058 | F03
F03_Walls_F03_059 | F03
F03_Walls_F03_060 | F03
F03_Walls_F03_061 | F03
F03_Walls_F03_062 | F03
F03_Walls_F03_063 | F03
F03_Walls_F03_064 | F03
F03_Walls_F03_065 | F03
F03_Walls_F03_066 | F03
F03_Walls_F03_067 | F03
F03_Walls_F03_068 | F03
F03_Walls_F03_069 | F03
F03_Walls_F03_070 | F03
F03_Walls_F03_071 | F03
F04_Walls_F04_001 | F04
F04_Walls_F04_002 | F04
F04_Walls_F04_003 | F04
F04_Walls_F04_004 | F04
F04_Walls_F04_005 | F04
F04_Walls_F04_006 | F04
F04_Walls_F04_007 | F04
F04_Walls_F04_008 | F04
F04_Walls_F04_009 | F04
F04_Walls_F04_010 | F04
F04_Walls_F04_011 | F04
F04_Walls_F04_012 | F04
F04_Walls_F04_013 | F04
F04_Walls_F04_014 | F04
F04_Walls_F04_015 | F04
F04_Walls_F04_016 | F04
F04_Walls_F04_017 | F04
F04_Walls_F04_018 | F04
F04_Walls_F04_019 | F04
F04_Walls_F04_020 | F04
F04_Walls_F04_021 | F04
F04_Walls_F04_022 | F04
F04_Walls_F04_023 | F04
F04_Walls_F04_024 | F04
F04_Walls_F04_025 | F04
F04_Walls_F04_026 | F04
F04_Walls_F04_027 | F04
F04_Walls_F04_028 | F04
F04_Walls_F04_029 | F04
F04_Walls_F04_030 | F04
F04_Walls_F04_031 | F04
F04_Walls_F04_032 | F04
F04_Walls_F04_033 | F04
F04_Walls_F04_034 | F04
F04_Walls_F04_035 | F04
F04_Walls_F04_036 | F04
F04_Walls_F04_037 | F04
F04_Walls_F04_038 | F04
F04_Walls_F04_039 | F04
F04_Walls_F04_040 | F04
F04_Walls_F04_041 | F04
F04_Walls_F04_042 | F04
F04_Walls_F04_043 | F04
F04_Walls_F04_044 | F04
F04_Walls_F04_045 | F04
F04_Walls_F04_046 | F04
F04_Walls_F04_047 | F04
F04_Walls_F04_048 | F04
F04_Walls_F04_049 | F04
F04_Walls_F04_050 | F04
F04_Walls_F04_051 | F04
F04_Walls_F04_052 | F04
F04_Walls_F04_053 | F04
F04_Walls_F04_054 | F04
F04_Walls_F04_055 | F04
F04_Walls_F04_056 | F04
F04_Walls_F04_057 | F04
F04_Walls_F04_058 | F04
F04_Walls_F04_059 | F04
F04_Walls_F04_060 | F04
F04_Walls_F04_061 | F04
F04_Walls_F04_062 | F04
F04_Walls_F04_063 | F04
F04_Walls_F04_064 | F04
F04_Walls_F04_065 | F04
F04_Walls_F04_066 | F04
F04_Walls_F04_067 | F04
F04_Walls_F04_068 | F04
F04_Walls_F04_069 | F04
F04_Walls_F04_070 | F04
F04_Walls_F04_071 | F04
F04_Walls_F04_072 | F04
F04_Walls_F04_073 | F04
F04_Walls_F04_074 | F04
F04_Walls_F04_075 | F04
F04_Walls_F04_076 | F04
F04_Walls_F04_077 | F04
F04_Walls_F04_078 | F04
F04_Walls_F04_079 | F04
F04_Walls_F04_080 | F04
F04_Walls_F04_081 | F04
F04_Walls_F04_082 | F04
F04_Walls_F04_083 | F04
F04_Walls_F04_084 | F04
F04_Walls_F04_085 | F04
F04_Walls_F04_086 | F04
F04_Walls_F04_087 | F04
F04_Walls_F04_088 | F04
F04_Walls_F04_089 | F04
F04_Walls_F04_090 | F04
F04_Walls_F04_091 | F04
F05_Walls_F05_001 | F05
F05_Walls_F05_002 | F05
F05_Walls_F05_003 | F05
F05_Walls_F05_004 | F05
F05_Walls_F05_005 | F05
F05_Walls_F05_006 | F05
F05_Walls_F05_007 | F05
F05_Walls_F05_008 | F05
F05_Walls_F05_009 | F05
F05_Walls_F05_010 | F05
F05_Walls_F05_011 | F05
F05_Walls_F05_012 | F05
F05_Walls_F05_013 | F05
F05_Walls_F05_014 | F05
F05_Walls_F05_015 | F05
F05_Walls_F05_016 | F05
F05_Walls_F05_017 | F05
F05_Walls_F05_018 | F05
F05_Walls_F05_019 | F05
F05_Walls_F05_020 | F05
F05_Walls_F05_021 | F05
F05_Walls_F05_022 | F05
F05_Walls_F05_023 | F05
F05_Walls_F05_024 | F05
F05_Walls_F05_025 | F05
F05_Walls_F05_026 | F05
F05_Walls_F05_027 | F05
F05_Walls_F05_028 | F05
F05_Walls_F05_029 | F05
F05_Walls_F05_030 | F05
F05_Walls_F05_031 | F05
F05_Walls_F05_032 | F05
F05_Walls_F05_033 | F05
F05_Walls_F05_034 | F05
F05_Walls_F05_035 | F05
F05_Walls_F05_036 | F05
F05_Walls_F05_037 | F05
F05_Walls_F05_038 | F05
F05_Walls_F05_039 | F05
F05_Walls_F05_040 | F05
F05_Walls_F05_041 | F05
F05_Walls_F05_042 | F05
F05_Walls_F05_043 | F05
F05_Walls_F05_044 | F05
F05_Walls_F05_045 | F05
F05_Walls_F05_046 | F05
F05_Walls_F05_047 | F05
F05_Walls_F05_048 | F05
F05_Walls_F05_049 | F05
F05_Walls_F05_050 | F05
F05_Walls_F05_051 | F05
F05_Walls_F05_052 | F05
F05_Walls_F05_053 | F05
F05_Walls_F05_054 | F05
F05_Walls_F05_055 | F05
F05_Walls_F05_056 | F05
F05_Walls_F05_057 | F05
F05_Walls_F05_058 | F05
F05_Walls_F05_059 | F05
F05_Walls_F05_060 | F05
F05_Walls_F05_061 | F05
F05_Walls_F05_062 | F05
F05_Walls_F05_063 | F05
F05_Walls_F05_064 | F05
F05_Walls_F05_065 | F05
F05_Walls_F05_066 | F05
F05_Walls_F05_067 | F05
F05_Walls_F05_068 | F05
F05_Walls_F05_069 | F05
F05_Walls_F05_070 | F05
F05_Walls_F05_071 | F05
F05_Walls_F05_072 | F05
F05_Walls_F05_073 | F05
F05_Walls_F05_074 | F05
F05_Walls_F05_075 | F05
F05_Walls_F05_076 | F05
F05_Walls_F05_077 | F05
F05_Walls_F05_078 | F05
F05_Walls_F05_079 | F05
F05_Walls_F05_080 | F05
F05_Walls_F05_081 | F05
F06_Walls_F06_001 | F06
F06_Walls_F06_002 | F06
F06_Walls_F06_003 | F06
F06_Walls_F06_004 | F06
F06_Walls_F06_005 | F06
F06_Walls_F06_006 | F06
F06_Walls_F06_007 | F06
F06_Walls_F06_008 | F06
F06_Walls_F06_009 | F06
F06_Walls_F06_010 | F06
F06_Walls_F06_011 | F06
F06_Walls_F06_012 | F06
F06_Walls_F06_013 | F06
F06_Walls_F06_014 | F06
F06_Walls_F06_015 | F06
F06_Walls_F06_016 | F06
F06_Walls_F06_017 | F06
F06_Walls_F06_018 | F06
F06_Walls_F06_019 | F06
F06_Walls_F06_020 | F06
F06_Walls_F06_021 | F06
F06_Walls_F06_022 | F06
F06_Walls_F06_023 | F06
F06_Walls_F06_024 | F06
F06_Walls_F06_025 | F06
F06_Walls_F06_026 | F06
F06_Walls_F06_027 | F06
F06_Walls_F06_028 | F06
F06_Walls_F06_029 | F06
F06_Walls_F06_030 | F06
F06_Walls_F06_031 | F06
F06_Walls_F06_032 | F06
F06_Walls_F06_033 | F06
F06_Walls_F06_034 | F06
F06_Walls_F06_035 | F06
F06_Walls_F06_036 | F06
F06_Walls_F06_037 | F06
F06_Walls_F06_038 | F06
F06_Walls_F06_039 | F06
F06_Walls_F06_040 | F06
F06_Walls_F06_041 | F06
F06_Walls_F06_042 | F06
F06_Walls_F06_043 | F06
F06_Walls_F06_044 | F06
F06_Walls_F06_045 | F06
F06_Walls_F06_046 | F06
F06_Walls_F06_047 | F06
F06_Walls_F06_048 | F06
F06_Walls_F06_049 | F06
F06_Walls_F06_050 | F06
F06_Walls_F06_051 | F06
F06_Walls_F06_052 | F06
F06_Walls_F06_053 | F06
F06_Walls_F06_054 | F06
F06_Walls_F06_055 | F06
F06_Walls_F06_056 | F06
F06_Walls_F06_057 | F06
F06_Walls_F06_058 | F06
F06_Walls_F06_059 | F06
F06_Walls_F06_060 | F06
F06_Walls_F06_061 | F06
F06_Walls_F06_062 | F06
F06_Walls_F06_063 | F06
F06_Walls_F06_064 | F06
F06_Walls_F06_065 | F06
F06_Walls_F06_066 | F06
F06_Walls_F06_067 | F06
F06_Walls_F06_068 | F06
F07_Walls_F07_001 | F07
F07_Walls_F07_002 | F07
F07_Walls_F07_003 | F07
F07_Walls_F07_004 | F07
F07_Walls_F07_005 | F07
F07_Walls_F07_006 | F07
F07_Walls_F07_007 | F07
F07_Walls_F07_008 | F07
F07_Walls_F07_009 | F07
F07_Walls_F07_010 | F07
F07_Walls_F07_011 | F07
F07_Walls_F07_012 | F07
F07_Walls_F07_013 | F07
F07_Walls_F07_014 | F07
F07_Walls_F07_015 | F07
F07_Walls_F07_016 | F07
F07_Walls_F07_017 | F07
F07_Walls_F07_018 | F07
F07_Walls_F07_019 | F07
F07_Walls_F07_020 | F07
F07_Walls_F07_021 | F07
F07_Walls_F07_022 | F07
F07_Walls_F07_023 | F07
F07_Walls_F07_024 | F07
F07_Walls_F07_025 | F07
F07_Walls_F07_026 | F07
F07_Walls_F07_027 | F07
F07_Walls_F07_028 | F07
F07_Walls_F07_029 | F07
F07_Walls_F07_030 | F07
F07_Walls_F07_031 | F07
F07_Walls_F07_032 | F07
F07_Walls_F07_033 | F07
F07_Walls_F07_034 | F07
F07_Walls_F07_035 | F07
F07_Walls_F07_036 | F07
F07_Walls_F07_037 | F07
F07_Walls_F07_038 | F07
F07_Walls_F07_039 | F07
F07_Walls_F07_040 | F07
F07_Walls_F07_041 | F07
F07_Walls_F07_042 | F07
F07_Walls_F07_043 | F07
F07_Walls_F07_044 | F07
F07_Walls_F07_045 | F07
F07_Walls_F07_046 | F07
F07_Walls_F07_047 | F07
F07_Walls_F07_048 | F07
F07_Walls_F07_049 | F07
F07_Walls_F07_050 | F07
F07_Walls_F07_051 | F07
F07_Walls_F07_052 | F07
F07_Walls_F07_053 | F07
F07_Walls_F07_054 | F07
F07_Walls_F07_055 | F07
F07_Walls_F07_056 | F07
F07_Walls_F07_057 | F07
F07_Walls_F07_058 | F07
F07_Walls_F07_059 | F07
F07_Walls_F07_060 | F07
F07_Walls_F07_061 | F07
F07_Walls_F07_062 | F07
F07_Walls_F07_063 | F07
F07_Walls_F07_064 | F07
F07_Walls_F07_065 | F07
F07_Walls_F07_066 | F07
F07_Walls_F07_067 | F07
F07_Walls_F07_068 | F07
F07_Walls_F07_069 | F07
F07_Walls_F07_070 | F07
F07_Walls_F07_071 | F07
F07_Walls_F07_072 | F07
F07_Walls_F07_073 | F07
F07_Walls_F07_074 | F07
F07_Walls_F07_075 | F07
F07_Walls_F07_076 | F07
F07_Walls_F07_077 | F07
F07_Walls_F07_078 | F07
F07_Walls_F07_079 | F07
F07_Walls_F07_080 | F07
F07_Walls_F07_081 | F07
F07_Walls_F07_082 | F07
F07_Walls_F07_083 | F07
F07_Walls_F07_084 | F07
F08_Walls_F08_001 | F08
F08_Walls_F08_002 | F08
F08_Walls_F08_003 | F08
F08_Walls_F08_004 | F08
F08_Walls_F08_005 | F08
F08_Walls_F08_006 | F08
F08_Walls_F08_007 | F08
F08_Walls_F08_008 | F08
F08_Walls_F08_009 | F08
F08_Walls_F08_010 | F08
F08_Walls_F08_011 | F08
F08_Walls_F08_012 | F08
F08_Walls_F08_013 | F08
F08_Walls_F08_014 | F08
F08_Walls_F08_015 | F08
F08_Walls_F08_016 | F08
F08_Walls_F08_017 | F08
F08_Walls_F08_018 | F08
F08_Walls_F08_019 | F08
F08_Walls_F08_020 | F08
F08_Walls_F08_021 | F08
F08_Walls_F08_022 | F08
F08_Walls_F08_023 | F08
F08_Walls_F08_024 | F08
F08_Walls_F08_025 | F08
F08_Walls_F08_026 | F08
F08_Walls_F08_027 | F08
F08_Walls_F08_028 | F08
F08_Walls_F08_029 | F08
F08_Walls_F08_030 | F08
F08_Walls_F08_031 | F08
F08_Walls_F08_032 | F08
F08_Walls_F08_033 | F08
F08_Walls_F08_034 | F08
F08_Walls_F08_035 | F08
F08_Walls_F08_036 | F08
F08_Walls_F08_037 | F08
F08_Walls_F08_038 | F08
F08_Walls_F08_039 | F08
F08_Walls_F08_040 | F08
F08_Walls_F08_041 | F08
F08_Walls_F08_042 | F08
F08_Walls_F08_043 | F08
F08_Walls_F08_044 | F08
F08_Walls_F08_045 | F08
F08_Walls_F08_046 | F08
F08_Walls_F08_047 | F08
F08_Walls_F08_048 | F08
F08_Walls_F08_049 | F08
F08_Walls_F08_050 | F08
F08_Walls_F08_051 | F08
F08_Walls_F08_052 | F08
F08_Walls_F08_053 | F08
F08_Walls_F08_054 | F08
F08_Walls_F08_055 | F08
F08_Walls_F08_056 | F08
F08_Walls_F08_057 | F08
F08_Walls_F08_058 | F08
F08_Walls_F08_059 | F08
F08_Walls_F08_060 | F08
F08_Walls_F08_061 | F08
F08_Walls_F08_062 | F08
F08_Walls_F08_063 | F08
F08_Walls_F08_064 | F08
F08_Walls_F08_065 | F08
F08_Walls_F08_066 | F08
F08_Walls_F08_067 | F08
F08_Walls_F08_068 | F08
F08_Walls_F08_069 | F08
F08_Walls_F08_070 | F08
F08_Walls_F08_071 | F08
F08_Walls_F08_072 | F08
F08_Walls_F08_073 | F08
F08_Walls_F08_074 | F08
F08_Walls_F08_075 | F08
F08_Walls_F08_076 | F08
F08_Walls_F08_077 | F08
F08_Walls_F08_078 | F08
F08_Walls_F08_079 | F08
F08_Walls_F08_080 | F08
F08_Walls_F08_081 | F08
F08_Walls_F08_082 | F08
F08_Walls_F08_083 | F08
F08_Walls_F08_084 | F08
F09_Walls_F09_001 | F09
F09_Walls_F09_002 | F09
F09_Walls_F09_003 | F09
F09_Walls_F09_004 | F09
F09_Walls_F09_005 | F09
F09_Walls_F09_006 | F09
F09_Walls_F09_007 | F09
F09_Walls_F09_008 | F09
F09_Walls_F09_009 | F09
F09_Walls_F09_010 | F09
F09_Walls_F09_011 | F09
F09_Walls_F09_012 | F09
F09_Walls_F09_013 | F09
F09_Walls_F09_014 | F09
F09_Walls_F09_015 | F09
F09_Walls_F09_016 | F09
F09_Walls_F09_017 | F09
F09_Walls_F09_018 | F09
F09_Walls_F09_019 | F09
F09_Walls_F09_020 | F09
F09_Walls_F09_021 | F09
F09_Walls_F09_022 | F09
F09_Walls_F09_023 | F09
F09_Walls_F09_024 | F09
F09_Walls_F09_025 | F09
F09_Walls_F09_026 | F09
F09_Walls_F09_027 | F09
F09_Walls_F09_028 | F09
F09_Walls_F09_029 | F09
F09_Walls_F09_030 | F09
F09_Walls_F09_031 | F09
F09_Walls_F09_032 | F09
F09_Walls_F09_033 | F09
F09_Walls_F09_034 | F09
F09_Walls_F09_035 | F09
F09_Walls_F09_036 | F09
F09_Walls_F09_037 | F09
F09_Walls_F09_038 | F09
F09_Walls_F09_039 | F09
F09_Walls_F09_040 | F09
F09_Walls_F09_041 | F09
F09_Walls_F09_042 | F09
F09_Walls_F09_043 | F09
F09_Walls_F09_044 | F09
F09_Walls_F09_045 | F09
F09_Walls_F09_046 | F09
F09_Walls_F09_047 | F09
F09_Walls_F09_048 | F09
F09_Walls_F09_049 | F09
F09_Walls_F09_050 | F09
F09_Walls_F09_051 | F09
F09_Walls_F09_052 | F09
F09_Walls_F09_053 | F09
F09_Walls_F09_054 | F09
F09_Walls_F09_055 | F09
F09_Walls_F09_056 | F09
F09_Walls_F09_057 | F09
F09_Walls_F09_058 | F09
F09_Walls_F09_059 | F09
F09_Walls_F09_060 | F09
F09_Walls_F09_061 | F09
F09_Walls_F09_062 | F09
F09_Walls_F09_063 | F09
F09_Walls_F09_064 | F09
F09_Walls_F09_065 | F09
F09_Walls_F09_066 | F09
F09_Walls_F09_067 | F09
F09_Walls_F09_068 | F09
F09_Walls_F09_069 | F09
F09_Walls_F09_070 | F09
F09_Walls_F09_071 | F09
F09_Walls_F09_072 | F09
F09_Walls_F09_073 | F09
F09_Walls_F09_074 | F09
F09_Walls_F09_075 | F09
F09_Walls_F09_076 | F09
F09_Walls_F09_077 | F09
F09_Walls_F09_078 | F09
F09_Walls_F09_079 | F09
F09_Walls_F09_080 | F09
F09_Walls_F09_081 | F09
F09_Walls_F09_082 | F09
F09_Walls_F09_083 | F09
F09_Walls_F09_084 | F09
F10_Walls_F10_001 | F10
F10_Walls_F10_002 | F10
F10_Walls_F10_003 | F10
F10_Walls_F10_004 | F10
F10_Walls_F10_005 | F10
F10_Walls_F10_006 | F10
F10_Walls_F10_007 | F10
F10_Walls_F10_008 | F10
F10_Walls_F10_009 | F10
F10_Walls_F10_010 | F10
F10_Walls_F10_011 | F10
F10_Walls_F10_012 | F10
F10_Walls_F10_013 | F10
F10_Walls_F10_014 | F10
F10_Walls_F10_015 | F10
F10_Walls_F10_016 | F10
F10_Walls_F10_017 | F10
F10_Walls_F10_018 | F10
F10_Walls_F10_019 | F10
F10_Walls_F10_020 | F10
F10_Walls_F10_021 | F10
F10_Walls_F10_022 | F10
F10_Walls_F10_023 | F10
F10_Walls_F10_024 | F10
F10_Walls_F10_025 | F10
F10_Walls_F10_026 | F10
F10_Walls_F10_027 | F10
F10_Walls_F10_028 | F10
F10_Walls_F10_029 | F10
F10_Walls_F10_030 | F10
F10_Walls_F10_031 | F10
F10_Walls_F10_032 | F10
F10_Walls_F10_033 | F10
F10_Walls_F10_034 | F10
F10_Walls_F10_035 | F10
F10_Walls_F10_036 | F10
F10_Walls_F10_037 | F10
F10_Walls_F10_038 | F10
F10_Walls_F10_039 | F10
F10_Walls_F10_040 | F10
F10_Walls_F10_041 | F10
F10_Walls_F10_042 | F10
F10_Walls_F10_043 | F10
F10_Walls_F10_044 | F10
F10_Walls_F10_045 | F10
F10_Walls_F10_046 | F10
F10_Walls_F10_047 | F10
F10_Walls_F10_048 | F10
F10_Walls_F10_049 | F10
F10_Walls_F10_050 | F10
F10_Walls_F10_051 | F10
F10_Walls_F10_052 | F10
F10_Walls_F10_053 | F10
F10_Walls_F10_054 | F10
F10_Walls_F10_055 | F10
F10_Walls_F10_056 | F10
F10_Walls_F10_057 | F10
F10_Walls_F10_058 | F10
F10_Walls_F10_059 | F10
F10_Walls_F10_060 | F10
F10_Walls_F10_061 | F10
F10_Walls_F10_062 | F10
F10_Walls_F10_063 | F10
F10_Walls_F10_064 | F10
F10_Walls_F10_065 | F10
F10_Walls_F10_066 | F10
F10_Walls_F10_067 | F10
F10_Walls_F10_068 | F10
F10_Walls_F10_069 | F10
F10_Walls_F10_070 | F10
F10_Walls_F10_071 | F10
F10_Walls_F10_072 | F10
F10_Walls_F10_073 | F10
F10_Walls_F10_074 | F10
F10_Walls_F10_075 | F10
F10_Walls_F10_076 | F10
F10_Walls_F10_077 | F10
F10_Walls_F10_078 | F10
F10_Walls_F10_079 | F10
F10_Walls_F10_080 | F10
F10_Walls_F10_081 | F10
F10_Walls_F10_082 | F10
F10_Walls_F10_083 | F10
F10_Walls_F10_084 | F10
F11_Walls_F11_001 | F11
F11_Walls_F11_002 | F11
F11_Walls_F11_003 | F11
F11_Walls_F11_004 | F11
F11_Walls_F11_005 | F11
F11_Walls_F11_006 | F11
F11_Walls_F11_007 | F11
F11_Walls_F11_008 | F11
F11_Walls_F11_009 | F11
F11_Walls_F11_010 | F11
F11_Walls_F11_011 | F11
F11_Walls_F11_012 | F11
F11_Walls_F11_013 | F11
F11_Walls_F11_014 | F11
F11_Walls_F11_015 | F11
F11_Walls_F11_016 | F11
F11_Walls_F11_017 | F11
F11_Walls_F11_018 | F11
F11_Walls_F11_019 | F11
F11_Walls_F11_020 | F11
F11_Walls_F11_021 | F11
F11_Walls_F11_022 | F11
F11_Walls_F11_023 | F11
F11_Walls_F11_024 | F11
F11_Walls_F11_025 | F11
F11_Walls_F11_026 | F11
F11_Walls_F11_027 | F11
F11_Walls_F11_028 | F11
F11_Walls_F11_029 | F11
F11_Walls_F11_030 | F11
F11_Walls_F11_031 | F11
F11_Walls_F11_032 | F11
F11_Walls_F11_033 | F11
F11_Walls_F11_034 | F11
F11_Walls_F11_035 | F11
F11_Walls_F11_036 | F11
F11_Walls_F11_037 | F11
F11_Walls_F11_038 | F11
F11_Walls_F11_039 | F11
F11_Walls_F11_040 | F11
F11_Walls_F11_041 | F11
F11_Walls_F11_042 | F11
F11_Walls_F11_043 | F11
F11_Walls_F11_044 | F11
F11_Walls_F11_045 | F11
F11_Walls_F11_046 | F11
F11_Walls_F11_047 | F11
F11_Walls_F11_048 | F11
F11_Walls_F11_049 | F11
F11_Walls_F11_050 | F11
F11_Walls_F11_051 | F11
F11_Walls_F11_052 | F11
F11_Walls_F11_053 | F11
F11_Walls_F11_054 | F11
F11_Walls_F11_055 | F11
F11_Walls_F11_056 | F11
F11_Walls_F11_057 | F11
F11_Walls_F11_058 | F11
F11_Walls_F11_059 | F11
F11_Walls_F11_060 | F11
F11_Walls_F11_061 | F11
F11_Walls_F11_062 | F11
F11_Walls_F11_063 | F11
F11_Walls_F11_064 | F11
F11_Walls_F11_065 | F11
F11_Walls_F11_066 | F11
F11_Walls_F11_067 | F11
F11_Walls_F11_068 | F11
F11_Walls_F11_069 | F11
F11_Walls_F11_070 | F11
F11_Walls_F11_071 | F11
F11_Walls_F11_072 | F11
F11_Walls_F11_073 | F11
F11_Walls_F11_074 | F11
F11_Walls_F11_075 | F11
F11_Walls_F11_076 | F11
F11_Walls_F11_077 | F11
F11_Walls_F11_078 | F11
F11_Walls_F11_079 | F11
F11_Walls_F11_080 | F11
F11_Walls_F11_081 | F11
F11_Walls_F11_082 | F11
F11_Walls_F11_083 | F11
F11_Walls_F11_084 | F11
F12_Walls_F12_001 | F12
F12_Walls_F12_002 | F12
F12_Walls_F12_003 | F12
F12_Walls_F12_004 | F12
F12_Walls_F12_005 | F12
F12_Walls_F12_006 | F12
F12_Walls_F12_007 | F12
F12_Walls_F12_008 | F12
F12_Walls_F12_009 | F12
F12_Walls_F12_010 | F12
F12_Walls_F12_011 | F12
F12_Walls_F12_012 | F12
F12_Walls_F12_013 | F12
F12_Walls_F12_014 | F12
F12_Walls_F12_015 | F12
F12_Walls_F12_016 | F12
F12_Walls_F12_017 | F12
F12_Walls_F12_018 | F12
F12_Walls_F12_019 | F12
F12_Walls_F12_020 | F12
F12_Walls_F12_021 | F12
F12_Walls_F12_022 | F12
F12_Walls_F12_023 | F12
F12_Walls_F12_024 | F12
F12_Walls_F12_025 | F12
F12_Walls_F12_026 | F12
F12_Walls_F12_027 | F12
F12_Walls_F12_028 | F12
F12_Walls_F12_029 | F12
F12_Walls_F12_030 | F12
F12_Walls_F12_031 | F12
F12_Walls_F12_032 | F12
F12_Walls_F12_033 | F12
F12_Walls_F12_034 | F12
F12_Walls_F12_035 | F12
F12_Walls_F12_036 | F12
F12_Walls_F12_037 | F12
F12_Walls_F12_038 | F12
F12_Walls_F12_039 | F12
F12_Walls_F12_040 | F12
F12_Walls_F12_041 | F12
F12_Walls_F12_042 | F12
F12_Walls_F12_043 | F12
F12_Walls_F12_044 | F12
F12_Walls_F12_045 | F12
F12_Walls_F12_046 | F12
F12_Walls_F12_047 | F12
F12_Walls_F12_048 | F12
F12_Walls_F12_049 | F12
F12_Walls_F12_050 | F12
F12_Walls_F12_051 | F12
F12_Walls_F12_052 | F12
F12_Walls_F12_053 | F12
F12_Walls_F12_054 | F12
F12_Walls_F12_055 | F12
F12_Walls_F12_056 | F12
F12_Walls_F12_057 | F12
F12_Walls_F12_058 | F12
F12_Walls_F12_059 | F12
F12_Walls_F12_060 | F12
F12_Walls_F12_061 | F12
F12_Walls_F12_062 | F12
F12_Walls_F12_063 | F12
F12_Walls_F12_064 | F12
F12_Walls_F12_065 | F12
F12_Walls_F12_066 | F12
F12_Walls_F12_067 | F12
F12_Walls_F12_068 | F12
F12_Walls_F12_069 | F12
F12_Walls_F12_070 | F12
F12_Walls_F12_071 | F12
F12_Walls_F12_072 | F12
F12_Walls_F12_073 | F12
F12_Walls_F12_074 | F12
F12_Walls_F12_075 | F12
F12_Walls_F12_076 | F12
F12_Walls_F12_077 | F12
F12_Walls_F12_078 | F12
F12_Walls_F12_079 | F12
F12_Walls_F12_080 | F12
F12_Walls_F12_081 | F12
F12_Walls_F12_082 | F12
F12_Walls_F12_083 | F12
F12_Walls_F12_084 | F12
F13_Walls_F13_001 | F13
F13_Walls_F13_002 | F13
F13_Walls_F13_003 | F13
F13_Walls_F13_004 | F13
F13_Walls_F13_005 | F13
F13_Walls_F13_006 | F13
F13_Walls_F13_007 | F13
F13_Walls_F13_008 | F13
F13_Walls_F13_009 | F13
F13_Walls_F13_010 | F13
F13_Walls_F13_011 | F13
F13_Walls_F13_012 | F13
F13_Walls_F13_013 | F13
F13_Walls_F13_014 | F13
F13_Walls_F13_015 | F13
F13_Walls_F13_016 | F13
F13_Walls_F13_017 | F13
F13_Walls_F13_018 | F13
F13_Walls_F13_019 | F13
F13_Walls_F13_020 | F13
F13_Walls_F13_021 | F13
F13_Walls_F13_022 | F13
F13_Walls_F13_023 | F13
F13_Walls_F13_024 | F13
F13_Walls_F13_025 | F13
F13_Walls_F13_026 | F13
F13_Walls_F13_027 | F13
F13_Walls_F13_028 | F13
F13_Walls_F13_029 | F13
F13_Walls_F13_030 | F13
F13_Walls_F13_031 | F13
F13_Walls_F13_032 | F13
F13_Walls_F13_033 | F13
F13_Walls_F13_034 | F13
F13_Walls_F13_035 | F13
F13_Walls_F13_036 | F13
F13_Walls_F13_037 | F13
F13_Walls_F13_038 | F13
F13_Walls_F13_039 | F13
F13_Walls_F13_040 | F13
F13_Walls_F13_041 | F13
F13_Walls_F13_042 | F13
F13_Walls_F13_043 | F13
F13_Walls_F13_044 | F13
F13_Walls_F13_045 | F13
F13_Walls_F13_046 | F13
F13_Walls_F13_047 | F13
F13_Walls_F13_048 | F13
F13_Walls_F13_049 | F13
F13_Walls_F13_050 | F13
F13_Walls_F13_051 | F13
F13_Walls_F13_052 | F13
F13_Walls_F13_053 | F13
F13_Walls_F13_054 | F13
F13_Walls_F13_055 | F13
F13_Walls_F13_056 | F13
F13_Walls_F13_057 | F13
F13_Walls_F13_058 | F13
F13_Walls_F13_059 | F13
F13_Walls_F13_060 | F13
F13_Walls_F13_061 | F13
F13_Walls_F13_062 | F13
F13_Walls_F13_063 | F13
F13_Walls_F13_064 | F13
F13_Walls_F13_065 | F13
F13_Walls_F13_066 | F13
F13_Walls_F13_067 | F13
F13_Walls_F13_068 | F13
F13_Walls_F13_069 | F13
F13_Walls_F13_070 | F13
F13_Walls_F13_071 | F13
F13_Walls_F13_072 | F13
F13_Walls_F13_073 | F13
F13_Walls_F13_074 | F13
F13_Walls_F13_075 | F13
F13_Walls_F13_076 | F13
F13_Walls_F13_077 | F13
F13_Walls_F13_078 | F13
F13_Walls_F13_079 | F13
F13_Walls_F13_080 | F13
F13_Walls_F13_081 | F13
F13_Walls_F13_082 | F13
F13_Walls_F13_083 | F13
F13_Walls_F13_084 | F13
F14_Walls_F14_001 | F14
F14_Walls_F14_002 | F14
F14_Walls_F14_003 | F14
F14_Walls_F14_004 | F14
F14_Walls_F14_005 | F14
F14_Walls_F14_006 | F14
F14_Walls_F14_007 | F14
F14_Walls_F14_008 | F14
F14_Walls_F14_009 | F14
F14_Walls_F14_010 | F14
F14_Walls_F14_011 | F14
F14_Walls_F14_012 | F14
F14_Walls_F14_013 | F14
F14_Walls_F14_014 | F14
F14_Walls_F14_015 | F14
F14_Walls_F14_016 | F14
F14_Walls_F14_017 | F14
F14_Walls_F14_018 | F14
F14_Walls_F14_019 | F14
F14_Walls_F14_020 | F14
F14_Walls_F14_021 | F14
F14_Walls_F14_022 | F14
F14_Walls_F14_023 | F14
F14_Walls_F14_024 | F14
F14_Walls_F14_025 | F14
F14_Walls_F14_026 | F14
F14_Walls_F14_027 | F14
F14_Walls_F14_028 | F14
F14_Walls_F14_029 | F14
F14_Walls_F14_030 | F14
F14_Walls_F14_031 | F14
F14_Walls_F14_032 | F14
F14_Walls_F14_033 | F14
F14_Walls_F14_034 | F14
F14_Walls_F14_035 | F14
F14_Walls_F14_036 | F14
F14_Walls_F14_037 | F14
F14_Walls_F14_038 | F14
F14_Walls_F14_039 | F14
F14_Walls_F14_040 | F14
F14_Walls_F14_041 | F14
F14_Walls_F14_042 | F14
F14_Walls_F14_043 | F14
F14_Walls_F14_044 | F14
F14_Walls_F14_045 | F14
F14_Walls_F14_046 | F14
F14_Walls_F14_047 | F14
F14_Walls_F14_048 | F14
F14_Walls_F14_049 | F14
F14_Walls_F14_050 | F14
F14_Walls_F14_051 | F14
F14_Walls_F14_052 | F14
F14_Walls_F14_053 | F14
F14_Walls_F14_054 | F14
F14_Walls_F14_055 | F14
F14_Walls_F14_056 | F14
F14_Walls_F14_057 | F14
F14_Walls_F14_058 | F14
F14_Walls_F14_059 | F14
F14_Walls_F14_060 | F14
F14_Walls_F14_061 | F14
F14_Walls_F14_062 | F14
F14_Walls_F14_063 | F14
F14_Walls_F14_064 | F14
F14_Walls_F14_065 | F14
F14_Walls_F14_066 | F14
F14_Walls_F14_067 | F14
F14_Walls_F14_068 | F14
F14_Walls_F14_069 | F14
F14_Walls_F14_070 | F14
F14_Walls_F14_071 | F14
F14_Walls_F14_072 | F14
F14_Walls_F14_073 | F14
F14_Walls_F14_074 | F14
F14_Walls_F14_075 | F14
F14_Walls_F14_076 | F14
F14_Walls_F14_077 | F14
F14_Walls_F14_078 | F14
F14_Walls_F14_079 | F14
F14_Walls_F14_080 | F14
F14_Walls_F14_081 | F14
F14_Walls_F14_082 | F14
F15_Walls_F15_001 | F15
F15_Walls_F15_002 | F15
F15_Walls_F15_003 | F15
F15_Walls_F15_004 | F15
F15_Walls_F15_005 | F15
F15_Walls_F15_006 | F15
F15_Walls_F15_007 | F15
F15_Walls_F15_008 | F15
F15_Walls_F15_009 | F15
F15_Walls_F15_010 | F15
F15_Walls_F15_011 | F15
F15_Walls_F15_012 | F15
F15_Walls_F15_013 | F15
F15_Walls_F15_014 | F15
F15_Walls_F15_015 | F15
F15_Walls_F15_016 | F15
F15_Walls_F15_017 | F15
F15_Walls_F15_018 | F15
F15_Walls_F15_019 | F15
F15_Walls_F15_020 | F15
F15_Walls_F15_021 | F15
F15_Walls_F15_022 | F15
F15_Walls_F15_023 | F15
F15_Walls_F15_024 | F15
F15_Walls_F15_025 | F15
F15_Walls_F15_026 | F15
F15_Walls_F15_027 | F15
F15_Walls_F15_028 | F15
F15_Walls_F15_029 | F15
F15_Walls_F15_030 | F15
F15_Walls_F15_031 | F15
F15_Walls_F15_032 | F15
F15_Walls_F15_033 | F15
F15_Walls_F15_034 | F15
F15_Walls_F15_035 | F15
F15_Walls_F15_036 | F15
F15_Walls_F15_037 | F15
F15_Walls_F15_038 | F15
F15_Walls_F15_039 | F15
F15_Walls_F15_040 | F15
F15_Walls_F15_041 | F15
F15_Walls_F15_042 | F15
F15_Walls_F15_043 | F15
F15_Walls_F15_044 | F15
F15_Walls_F15_045 | F15
F15_Walls_F15_046 | F15
F15_Walls_F15_047 | F15
F15_Walls_F15_048 | F15
F15_Walls_F15_049 | F15
F15_Walls_F15_050 | F15
F15_Walls_F15_051 | F15
F15_Walls_F15_052 | F15
F15_Walls_F15_053 | F15
F15_Walls_F15_054 | F15
F15_Walls_F15_055 | F15
F15_Walls_F15_056 | F15
F15_Walls_F15_057 | F15
F15_Walls_F15_058 | F15
F15_Walls_F15_059 | F15
F15_Walls_F15_060 | F15
F15_Walls_F15_061 | F15
F15_Walls_F15_062 | F15
F15_Walls_F15_063 | F15
F15_Walls_F15_064 | F15
F15_Walls_F15_065 | F15
F15_Walls_F15_066 | F15
F15_Walls_F15_067 | F15
F15_Walls_F15_068 | F15
F15_Walls_F15_069 | F15
F15_Walls_F15_070 | F15
F15_Walls_F15_071 | F15
F15_Walls_F15_072 | F15
F15_Walls_F15_073 | F15
F15_Walls_F15_074 | F15
F15_Walls_F15_075 | F15
F15_Walls_F15_076 | F15
F15_Walls_F15_077 | F15
F15_Walls_F15_078 | F15
F15_Walls_F15_079 | F15
F15_Walls_F15_080 | F15
F15_Walls_F15_081 | F15
F15_Walls_F15_082 | F15
F16_Walls_F16_001 | F16
F16_Walls_F16_002 | F16
F16_Walls_F16_003 | F16
F16_Walls_F16_004 | F16
F16_Walls_F16_005 | F16
F16_Walls_F16_006 | F16
F16_Walls_F16_007 | F16
F16_Walls_F16_008 | F16
F16_Walls_F16_009 | F16
F16_Walls_F16_010 | F16
F16_Walls_F16_011 | F16
F16_Walls_F16_012 | F16
F16_Walls_F16_013 | F16
F16_Walls_F16_014 | F16
F16_Walls_F16_015 | F16
F16_Walls_F16_016 | F16
F16_Walls_F16_017 | F16
F16_Walls_F16_018 | F16
F16_Walls_F16_019 | F16
F16_Walls_F16_020 | F16
F16_Walls_F16_021 | F16
F16_Walls_F16_022 | F16
F16_Walls_F16_023 | F16
F16_Walls_F16_024 | F16
F16_Walls_F16_025 | F16
F16_Walls_F16_026 | F16
F16_Walls_F16_027 | F16
F16_Walls_F16_028 | F16
F16_Walls_F16_029 | F16
F16_Walls_F16_030 | F16
F16_Walls_F16_031 | F16
F16_Walls_F16_032 | F16
F16_Walls_F16_033 | F16
F16_Walls_F16_034 | F16
F16_Walls_F16_035 | F16
F16_Walls_F16_036 | F16
F16_Walls_F16_037 | F16
F16_Walls_F16_038 | F16
F16_Walls_F16_039 | F16
F16_Walls_F16_040 | F16
F16_Walls_F16_041 | F16
F16_Walls_F16_042 | F16
F16_Walls_F16_043 | F16
F16_Walls_F16_044 | F16
F16_Walls_F16_045 | F16
F16_Walls_F16_046 | F16
F16_Walls_F16_047 | F16
F16_Walls_F16_048 | F16
F16_Walls_F16_049 | F16
F16_Walls_F16_050 | F16
F16_Walls_F16_051 | F16
F16_Walls_F16_052 | F16
F16_Walls_F16_053 | F16
F16_Walls_F16_054 | F16
F16_Walls_F16_055 | F16
F16_Walls_F16_056 | F16
F16_Walls_F16_057 | F16
F16_Walls_F16_058 | F16
F16_Walls_F16_059 | F16
F16_Walls_F16_060 | F16
F16_Walls_F16_061 | F16
F16_Walls_F16_062 | F16
F16_Walls_F16_063 | F16
F16_Walls_F16_064 | F16
F16_Walls_F16_065 | F16
F16_Walls_F16_066 | F16
F16_Walls_F16_067 | F16
F16_Walls_F16_068 | F16
F16_Walls_F16_069 | F16
F16_Walls_F16_070 | F16
F16_Walls_F16_071 | F16
F16_Walls_F16_072 | F16
F16_Walls_F16_073 | F16
F16_Walls_F16_074 | F16
F16_Walls_F16_075 | F16
F16_Walls_F16_076 | F16
F16_Walls_F16_077 | F16
F16_Walls_F16_078 | F16
F16_Walls_F16_079 | F16
F16_Walls_F16_080 | F16
F16_Walls_F16_081 | F16
F16_Walls_F16_082 | F16
F17_Walls_F17_001 | F17
F17_Walls_F17_002 | F17
F17_Walls_F17_003 | F17
F17_Walls_F17_004 | F17
F17_Walls_F17_005 | F17
F17_Walls_F17_006 | F17
F17_Walls_F17_007 | F17
F17_Walls_F17_008 | F17
F17_Walls_F17_009 | F17
F17_Walls_F17_010 | F17
F17_Walls_F17_011 | F17
F17_Walls_F17_012 | F17
F17_Walls_F17_013 | F17
F17_Walls_F17_014 | F17
F17_Walls_F17_015 | F17
F17_Walls_F17_016 | F17
F17_Walls_F17_017 | F17
F17_Walls_F17_018 | F17
F17_Walls_F17_019 | F17
F17_Walls_F17_020 | F17
F17_Walls_F17_021 | F17
F17_Walls_F17_022 | F17
F17_Walls_F17_023 | F17
F17_Walls_F17_024 | F17
F17_Walls_F17_025 | F17
F17_Walls_F17_026 | F17
F17_Walls_F17_027 | F17
F17_Walls_F17_028 | F17
F17_Walls_F17_029 | F17
F17_Walls_F17_030 | F17
F17_Walls_F17_031 | F17
F17_Walls_F17_032 | F17
F17_Walls_F17_033 | F17
F17_Walls_F17_034 | F17
F17_Walls_F17_035 | F17
F17_Walls_F17_036 | F17
F17_Walls_F17_037 | F17
F17_Walls_F17_038 | F17
F17_Walls_F17_039 | F17
F17_Walls_F17_040 | F17
F17_Walls_F17_041 | F17
F17_Walls_F17_042 | F17
F17_Walls_F17_043 | F17
F17_Walls_F17_044 | F17
F17_Walls_F17_045 | F17
F17_Walls_F17_046 | F17
F17_Walls_F17_047 | F17
F17_Walls_F17_048 | F17
F17_Walls_F17_049 | F17
F17_Walls_F17_050 | F17
F17_Walls_F17_051 | F17
F17_Walls_F17_052 | F17
F17_Walls_F17_053 | F17
F17_Walls_F17_054 | F17
F17_Walls_F17_055 | F17
F17_Walls_F17_056 | F17
F17_Walls_F17_057 | F17
F17_Walls_F17_058 | F17
F17_Walls_F17_059 | F17
F17_Walls_F17_060 | F17
F17_Walls_F17_061 | F17
F17_Walls_F17_062 | F17
F17_Walls_F17_063 | F17
F17_Walls_F17_064 | F17
F17_Walls_F17_065 | F17
F17_Walls_F17_066 | F17
F17_Walls_F17_067 | F17
F17_Walls_F17_068 | F17
F17_Walls_F17_069 | F17
F17_Walls_F17_070 | F17
F17_Walls_F17_071 | F17
F17_Walls_F17_072 | F17
F17_Walls_F17_073 | F17
F17_Walls_F17_074 | F17
F17_Walls_F17_075 | F17
F17_Walls_F17_076 | F17
F17_Walls_F17_077 | F17
F17_Walls_F17_078 | F17
F17_Walls_F17_079 | F17
F17_Walls_F17_080 | F17
F17_Walls_F17_081 | F17
F17_Walls_F17_082 | F17
F17_Walls_F17_083 | F17
F17_Walls_F17_084 | F17
F17_Walls_F17_085 | F17
F17_Walls_F17_086 | F17
F17_Walls_F17_087 | F17
F17_Walls_F17_088 | F17
F17_Walls_F17_089 | F17
F17_Walls_F17_090 | F17
F17_Walls_F17_091 | F17
F17_Walls_F17_092 | F17
F17_Walls_F17_093 | F17
F17_Walls_F17_094 | F17
F17_Walls_F17_095 | F17
F17_Walls_F17_096 | F17
F17_Walls_F17_097 | F17
F18_Walls_F18_001 | F18
F18_Walls_F18_002 | F18
F18_Walls_F18_003 | F18
F18_Walls_F18_004 | F18
F18_Walls_F18_005 | F18
F18_Walls_F18_006 | F18
F18_Walls_F18_007 | F18
F18_Walls_F18_008 | F18
F18_Walls_F18_009 | F18
F18_Walls_F18_010 | F18
F18_Walls_F18_011 | F18
F18_Walls_F18_012 | F18
F18_Walls_F18_013 | F18
F18_Walls_F18_014 | F18
F18_Walls_F18_015 | F18
F18_Walls_F18_016 | F18
F18_Walls_F18_017 | F18
F18_Walls_F18_018 | F18
F18_Walls_F18_019 | F18
F18_Walls_F18_020 | F18
F18_Walls_F18_021 | F18
F18_Walls_F18_022 | F18
F18_Walls_F18_023 | F18
F18_Walls_F18_024 | F18
F18_Walls_F18_025 | F18
F18_Walls_F18_026 | F18
F18_Walls_F18_027 | F18
F18_Walls_F18_028 | F18
F18_Walls_F18_029 | F18
F18_Walls_F18_030 | F18
F18_Walls_F18_031 | F18
F18_Walls_F18_032 | F18
F18_Walls_F18_033 | F18
F18_Walls_F18_034 | F18
F18_Walls_F18_035 | F18
F18_Walls_F18_036 | F18
F18_Walls_F18_037 | F18
F18_Walls_F18_038 | F18
F18_Walls_F18_039 | F18
F18_Walls_F18_040 | F18
F18_Walls_F18_041 | F18
F18_Walls_F18_042 | F18
F18_Walls_F18_043 | F18
F18_Walls_F18_044 | F18
F18_Walls_F18_045 | F18
F18_Walls_F18_046 | F18
F18_Walls_F18_047 | F18
F18_Walls_F18_048 | F18
F18_Walls_F18_049 | F18
F18_Walls_F18_050 | F18
F18_Walls_F18_051 | F18
F18_Walls_F18_052 | F18
F18_Walls_F18_053 | F18
F18_Walls_F18_054 | F18
F18_Walls_F18_055 | F18
F18_Walls_F18_056 | F18
F18_Walls_F18_057 | F18
F18_Walls_F18_058 | F18
F18_Walls_F18_059 | F18
F18_Walls_F18_060 | F18
F18_Walls_F18_061 | F18
F18_Walls_F18_062 | F18
F18_Walls_F18_063 | F18
F18_Walls_F18_064 | F18
F18_Walls_F18_065 | F18
F18_Walls_F18_066 | F18
F18_Walls_F18_067 | F18
F18_Walls_F18_068 | F18
F18_Walls_F18_069 | F18
F18_Walls_F18_070 | F18
F18_Walls_F18_071 | F18
F18_Walls_F18_072 | F18
F18_Walls_F18_073 | F18
F18_Walls_F18_074 | F18
F18_Walls_F18_075 | F18
F18_Walls_F18_076 | F18
F18_Walls_F18_077 | F18
F18_Walls_F18_078 | F18
F18_Walls_F18_079 | F18
F18_Walls_F18_080 | F18
F18_Walls_F18_081 | F18
F18_Walls_F18_082 | F18
F18_Walls_F18_083 | F18
F18_Walls_F18_084 | F18
F18_Walls_F18_085 | F18
F18_Walls_F18_086 | F18
F18_Walls_F18_087 | F18
F18_Walls_F18_088 | F18
F18_Walls_F18_089 | F18
F19_Walls_F19_001 | F19
F19_Walls_F19_002 | F19
F19_Walls_F19_003 | F19
F19_Walls_F19_004 | F19
F19_Walls_F19_005 | F19
F19_Walls_F19_006 | F19
F19_Walls_F19_007 | F19
F19_Walls_F19_008 | F19
F19_Walls_F19_009 | F19
F19_Walls_F19_010 | F19
F19_Walls_F19_011 | F19
F19_Walls_F19_012 | F19
F19_Walls_F19_013 | F19
F19_Walls_F19_014 | F19
F19_Walls_F19_015 | F19
F19_Walls_F19_016 | F19
F19_Walls_F19_017 | F19
F19_Walls_F19_018 | F19
F19_Walls_F19_019 | F19
F19_Walls_F19_020 | F19
F19_Walls_F19_021 | F19
F19_Walls_F19_022 | F19
F19_Walls_F19_023 | F19
F19_Walls_F19_024 | F19
F19_Walls_F19_025 | F19
F19_Walls_F19_026 | F19
F19_Walls_F19_027 | F19
F19_Walls_F19_028 | F19
F19_Walls_F19_029 | F19
F19_Walls_F19_030 | F19
F19_Walls_F19_031 | F19
F19_Walls_F19_032 | F19
F19_Walls_F19_033 | F19
F19_Walls_F19_034 | F19
F19_Walls_F19_035 | F19
F19_Walls_F19_036 | F19
F19_Walls_F19_037 | F19
F19_Walls_F19_038 | F19
F19_Walls_F19_039 | F19
F19_Walls_F19_040 | F19
F19_Walls_F19_041 | F19
F19_Walls_F19_042 | F19
F19_Walls_F19_043 | F19
F19_Walls_F19_044 | F19
F19_Walls_F19_045 | F19
F19_Walls_F19_046 | F19
F19_Walls_F19_047 | F19
F19_Walls_F19_048 | F19
F19_Walls_F19_049 | F19
F19_Walls_F19_050 | F19
F19_Walls_F19_051 | F19
F19_Walls_F19_052 | F19
F19_Walls_F19_053 | F19
F19_Walls_F19_054 | F19
F19_Walls_F19_055 | F19
F19_Walls_F19_056 | F19
F19_Walls_F19_057 | F19
F19_Walls_F19_058 | F19
F19_Walls_F19_059 | F19
F19_Walls_F19_060 | F19
F19_Walls_F19_061 | F19
F19_Walls_F19_062 | F19
F19_Walls_F19_063 | F19
RF_Walls_RF_001 | RF
RF_Walls_RF_002 | RF
RF_Walls_RF_003 | RF
RF_Walls_RF_004 | RF
RF_Walls_RF_005 | RF
RF_Walls_RF_006 | RF
RF_Walls_RF_007 | RF
RF_Walls_RF_008 | RF
RF_Walls_RF_009 | RF
RF_Walls_RF_010 | RF
RF_Walls_RF_011 | RF
RF_Walls_RF_012 | RF
RF_Walls_RF_013 | RF
RF_Walls_RF_014 | RF
RF_Walls_RF_015 | RF
RF_Walls_RF_016 | RF
RF_Walls_RF_017 | RF
RF_Walls_RF_018 | RF
RF_Walls_RF_019 | RF
RF_Walls_RF_020 | RF
